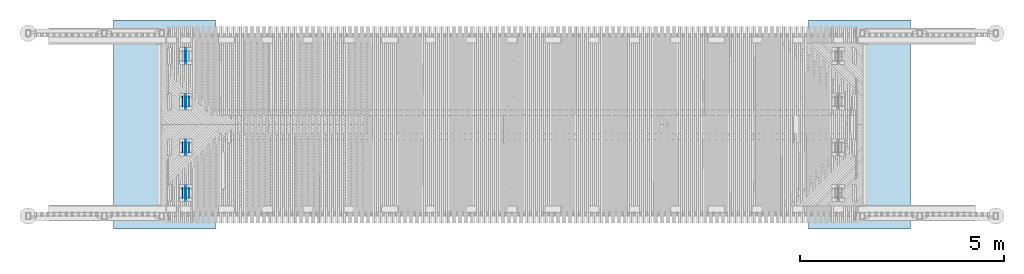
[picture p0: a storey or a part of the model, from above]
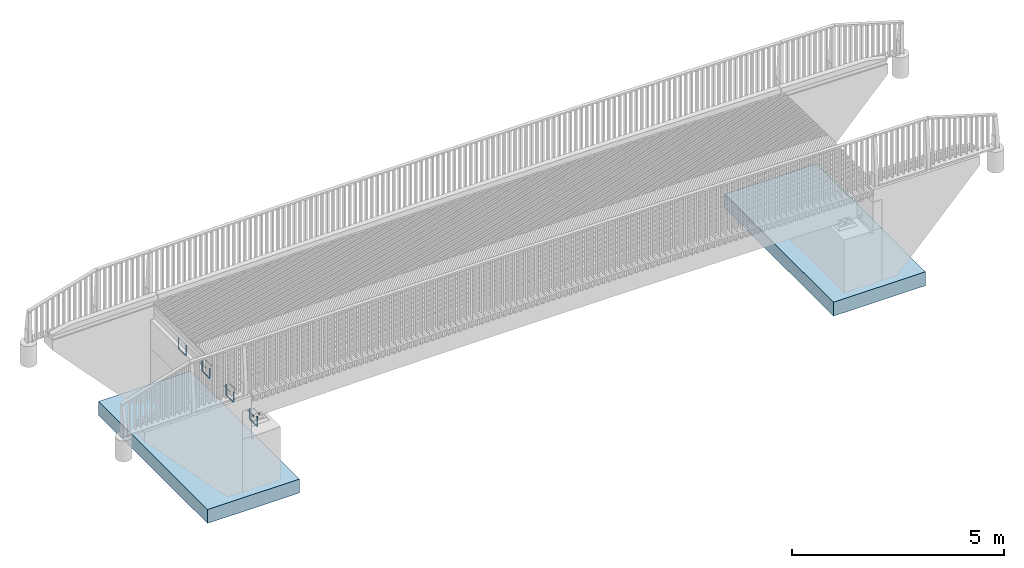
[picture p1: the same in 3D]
Properties of the parts of a building model (IFC2X3), part 2 of 2

# IfcBeam: 50*50 (546)
Name | Bottom elevation | Top elevation | Weight (kg) | Area per tons (m2) | Net surface area (m2) | Height (mm) | Tekla Quantity, Length (mm) | BaseQuantities, Length (mm) | OuterSurfaceArea (m2) | NetVolume (m3) | NetWeight (kg)
3 x BEAM | +3.165 | +3.261 | 4.1 | 135.1 | 0.7 | 50 | 2880.8 | 2880.76 | 0.572941 | 0.00707335 | 4.24401
3 x BEAM | +3.164 | +3.261 | 4.1 | 135.1 | 0.7 | 50 | 2880.8 | 2880.77 | 0.572949 | 0.0070735 | 4.2441
3 x BEAM | +3.164 | +3.261 | 4.1 | 135.1 | 0.7 | 50 | 2880.8 | 2880.76 | 0.572941 | 0.00707335 | 4.24401
3 x BEAM | +3.163 | +3.260 | 4.1 | 135.1 | 0.7 | 50 | 2880.8 | 2880.77 | 0.572949 | 0.0070735 | 4.2441
3 x BEAM | +3.163 | +3.260 | 4.1 | 135.1 | 0.7 | 50 | 2880.8 | 2880.76 | 0.572941 | 0.00707335 | 4.24401
2 x BEAM | +3.162 | +3.260 | 4.1 | 135.1 | 0.7 | 50 | 2880.8 | 2880.77 | 0.572949 | 0.0070735 | 4.2441
2 x BEAM | +3.162 | +3.260 | 4.1 | 135.1 | 0.7 | 50 | 2880.8 | 2880.76 | 0.572941 | 0.00707335 | 4.24401
2 x BEAM | +3.161 | +3.260 | 4.1 | 135.1 | 0.7 | 50 | 2880.8 | 2880.77 | 0.572949 | 0.0070735 | 4.2441
2 x BEAM | +3.161 | +3.260 | 4.1 | 135.1 | 0.7 | 50 | 2880.8 | 2880.76 | 0.572941 | 0.00707335 | 4.24401
BEAM | +3.161 | +3.259 | 4.1 | 135.1 | 0.7 | 50 | 2880.8 | 2880.77 | 0.572949 | 0.0070735 | 4.2441
BEAM | +3.161 | +3.259 | 4.1 | 135.1 | 0.7 | 50 | 2880.8 | 2880.76 | 0.572941 | 0.00707335 | 4.24401
2 x BEAM | +3.160 | +3.259 | 4.1 | 135.1 | 0.7 | 50 | 2880.8 | 2880.77 | 0.572949 | 0.0070735 | 4.2441
2 x BEAM | +3.160 | +3.259 | 4.1 | 135.1 | 0.7 | 50 | 2880.8 | 2880.76 | 0.572941 | 0.00707335 | 4.24401
2 x BEAM | +3.159 | +3.259 | 4.1 | 135.1 | 0.7 | 50 | 2880.8 | 2880.77 | 0.572949 | 0.0070735 | 4.2441
2 x BEAM | +3.159 | +3.259 | 4.1 | 135.1 | 0.7 | 50 | 2880.8 | 2880.76 | 0.572941 | 0.00707335 | 4.24401
2 x BEAM | +3.158 | +3.258 | 4.1 | 135.1 | 0.7 | 50 | 2880.8 | 2880.77 | 0.572949 | 0.0070735 | 4.2441
2 x BEAM | +3.158 | +3.258 | 4.1 | 135.1 | 0.7 | 50 | 2880.8 | 2880.76 | 0.572941 | 0.00707335 | 4.24401
3 x BEAM | +3.157 | +3.258 | 4.1 | 135.1 | 0.7 | 50 | 2880.8 | 2880.77 | 0.572949 | 0.0070735 | 4.2441
3 x BEAM | +3.157 | +3.258 | 4.1 | 135.1 | 0.7 | 50 | 2880.8 | 2880.76 | 0.572941 | 0.00707335 | 4.24401
2 x BEAM | +3.156 | +3.257 | 4.1 | 135.1 | 0.7 | 50 | 2880.8 | 2880.77 | 0.572949 | 0.0070735 | 4.2441
2 x BEAM | +3.156 | +3.257 | 4.1 | 135.1 | 0.7 | 50 | 2880.8 | 2880.76 | 0.572941 | 0.00707335 | 4.24401
BEAM | +3.155 | +3.257 | 4.1 | 135.1 | 0.7 | 50 | 2880.8 | 2880.77 | 0.572949 | 0.0070735 | 4.2441
BEAM | +3.155 | +3.257 | 4.1 | 135.1 | 0.7 | 50 | 2880.8 | 2880.76 | 0.572941 | 0.00707335 | 4.24401
BEAM | +3.154 | +3.257 | 4.1 | 135.1 | 0.7 | 50 | 2880.8 | 2880.77 | 0.572949 | 0.0070735 | 4.2441
BEAM | +3.154 | +3.257 | 4.1 | 135.1 | 0.7 | 50 | 2880.8 | 2880.76 | 0.572941 | 0.00707335 | 4.24401
BEAM | +3.154 | +3.256 | 4.1 | 135.1 | 0.7 | 50 | 2880.8 | 2880.77 | 0.572949 | 0.0070735 | 4.2441
BEAM | +3.154 | +3.256 | 4.1 | 135.1 | 0.7 | 50 | 2880.8 | 2880.76 | 0.572941 | 0.00707335 | 4.24401
2 x BEAM | +3.153 | +3.256 | 4.1 | 135.1 | 0.7 | 50 | 2880.8 | 2880.77 | 0.572949 | 0.0070735 | 4.2441
2 x BEAM | +3.153 | +3.256 | 4.1 | 135.1 | 0.7 | 50 | 2880.8 | 2880.76 | 0.572941 | 0.00707335 | 4.24401
2 x BEAM | +3.152 | +3.255 | 4.1 | 135.1 | 0.7 | 50 | 2880.8 | 2880.77 | 0.572949 | 0.0070735 | 4.2441
2 x BEAM | +3.152 | +3.255 | 4.1 | 135.1 | 0.7 | 50 | 2880.8 | 2880.76 | 0.572941 | 0.00707335 | 4.24401
BEAM | +3.151 | +3.255 | 4.1 | 135.1 | 0.7 | 50 | 2880.8 | 2880.77 | 0.572949 | 0.0070735 | 4.2441
BEAM | +3.151 | +3.255 | 4.1 | 135.1 | 0.7 | 50 | 2880.8 | 2880.76 | 0.572941 | 0.00707335 | 4.24401
BEAM | +3.151 | +3.254 | 4.1 | 135.1 | 0.7 | 50 | 2880.8 | 2880.77 | 0.572949 | 0.0070735 | 4.2441
BEAM | +3.151 | +3.254 | 4.1 | 135.1 | 0.7 | 50 | 2880.8 | 2880.76 | 0.572941 | 0.00707335 | 4.24401
BEAM | +3.150 | +3.254 | 4.1 | 135.1 | 0.7 | 50 | 2880.8 | 2880.77 | 0.572949 | 0.0070735 | 4.2441
BEAM | +3.150 | +3.254 | 4.1 | 135.1 | 0.7 | 50 | 2880.8 | 2880.76 | 0.572941 | 0.00707335 | 4.24401
BEAM | +3.149 | +3.254 | 4.1 | 135.1 | 0.7 | 50 | 2880.8 | 2880.77 | 0.572949 | 0.0070735 | 4.2441
BEAM | +3.149 | +3.254 | 4.1 | 135.1 | 0.7 | 50 | 2880.8 | 2880.76 | 0.572941 | 0.00707335 | 4.24401
BEAM | +3.149 | +3.253 | 4.1 | 135.1 | 0.7 | 50 | 2880.8 | 2880.77 | 0.572949 | 0.0070735 | 4.2441
BEAM | +3.149 | +3.253 | 4.1 | 135.1 | 0.7 | 50 | 2880.8 | 2880.76 | 0.572941 | 0.00707335 | 4.24401
2 x BEAM | +3.148 | +3.253 | 4.1 | 135.1 | 0.7 | 50 | 2880.8 | 2880.77 | 0.572949 | 0.0070735 | 4.2441
2 x BEAM | +3.148 | +3.253 | 4.1 | 135.1 | 0.7 | 50 | 2880.8 | 2880.76 | 0.572941 | 0.00707335 | 4.24401
BEAM | +3.147 | +3.252 | 4.1 | 135.1 | 0.7 | 50 | 2880.8 | 2880.77 | 0.572949 | 0.0070735 | 4.2441
BEAM | +3.147 | +3.252 | 4.1 | 135.1 | 0.7 | 50 | 2880.8 | 2880.76 | 0.572941 | 0.00707335 | 4.24401
BEAM | +3.146 | +3.252 | 4.1 | 135.1 | 0.7 | 50 | 2880.8 | 2880.77 | 0.572949 | 0.0070735 | 4.2441
BEAM | +3.146 | +3.252 | 4.1 | 135.1 | 0.7 | 50 | 2880.8 | 2880.76 | 0.572941 | 0.00707335 | 4.24401
BEAM | +3.146 | +3.251 | 4.1 | 135.1 | 0.7 | 50 | 2880.8 | 2880.77 | 0.572949 | 0.0070735 | 4.2441
BEAM | +3.146 | +3.251 | 4.1 | 135.1 | 0.7 | 50 | 2880.8 | 2880.76 | 0.572941 | 0.00707335 | 4.24401
BEAM | +3.145 | +3.251 | 4.1 | 135.1 | 0.7 | 50 | 2880.8 | 2880.77 | 0.572949 | 0.0070735 | 4.2441
BEAM | +3.145 | +3.251 | 4.1 | 135.1 | 0.7 | 50 | 2880.8 | 2880.76 | 0.572941 | 0.00707335 | 4.24401
BEAM | +3.144 | +3.251 | 4.1 | 135.1 | 0.7 | 50 | 2880.8 | 2880.77 | 0.572949 | 0.0070735 | 4.2441
BEAM | +3.144 | +3.251 | 4.1 | 135.1 | 0.7 | 50 | 2880.8 | 2880.76 | 0.572941 | 0.00707335 | 4.24401
BEAM | +3.144 | +3.250 | 4.1 | 135.1 | 0.7 | 50 | 2880.8 | 2880.77 | 0.572949 | 0.0070735 | 4.2441
BEAM | +3.144 | +3.250 | 4.1 | 135.1 | 0.7 | 50 | 2880.8 | 2880.76 | 0.572941 | 0.00707335 | 4.24401
BEAM | +3.143 | +3.250 | 4.1 | 135.1 | 0.7 | 50 | 2880.8 | 2880.77 | 0.572949 | 0.0070735 | 4.2441
BEAM | +3.143 | +3.250 | 4.1 | 135.1 | 0.7 | 50 | 2880.8 | 2880.76 | 0.572941 | 0.00707335 | 4.24401
2 x BEAM | +3.142 | +3.249 | 4.1 | 135.1 | 0.7 | 50 | 2880.8 | 2880.77 | 0.572949 | 0.0070735 | 4.2441
2 x BEAM | +3.142 | +3.249 | 4.1 | 135.1 | 0.7 | 50 | 2880.8 | 2880.76 | 0.572941 | 0.00707335 | 4.24401
BEAM | +3.141 | +3.248 | 4.1 | 135.1 | 0.7 | 50 | 2880.8 | 2880.77 | 0.572949 | 0.0070735 | 4.2441
BEAM | +3.141 | +3.248 | 4.1 | 135.1 | 0.7 | 50 | 2880.8 | 2880.76 | 0.572941 | 0.00707335 | 4.24401
BEAM | +3.140 | +3.248 | 4.1 | 135.1 | 0.7 | 50 | 2880.8 | 2880.77 | 0.572949 | 0.0070735 | 4.2441
BEAM | +3.140 | +3.248 | 4.1 | 135.1 | 0.7 | 50 | 2880.8 | 2880.76 | 0.572941 | 0.00707335 | 4.24401
BEAM | +3.140 | +3.247 | 4.1 | 135.1 | 0.7 | 50 | 2880.8 | 2880.77 | 0.572949 | 0.0070735 | 4.2441
BEAM | +3.140 | +3.247 | 4.1 | 135.1 | 0.7 | 50 | 2880.8 | 2880.76 | 0.572941 | 0.00707335 | 4.24401
BEAM | +3.139 | +3.247 | 4.1 | 135.1 | 0.7 | 50 | 2880.8 | 2880.77 | 0.572949 | 0.0070735 | 4.2441
BEAM | +3.139 | +3.247 | 4.1 | 135.1 | 0.7 | 50 | 2880.8 | 2880.76 | 0.572941 | 0.00707335 | 4.24401
BEAM | +3.138 | +3.246 | 4.1 | 135.1 | 0.7 | 50 | 2880.8 | 2880.77 | 0.572949 | 0.0070735 | 4.2441
BEAM | +3.138 | +3.246 | 4.1 | 135.1 | 0.7 | 50 | 2880.8 | 2880.76 | 0.572941 | 0.00707335 | 4.24401
BEAM | +3.137 | +3.246 | 4.1 | 135.1 | 0.7 | 50 | 2880.8 | 2880.77 | 0.572949 | 0.0070735 | 4.2441
BEAM | +3.137 | +3.246 | 4.1 | 135.1 | 0.7 | 50 | 2880.8 | 2880.76 | 0.572941 | 0.00707335 | 4.24401
BEAM | +3.137 | +3.245 | 4.1 | 135.1 | 0.7 | 50 | 2880.8 | 2880.77 | 0.572949 | 0.0070735 | 4.2441
BEAM | +3.137 | +3.245 | 4.1 | 135.1 | 0.7 | 50 | 2880.8 | 2880.76 | 0.572941 | 0.00707335 | 4.24401
BEAM | +3.136 | +3.245 | 4.1 | 135.1 | 0.7 | 50 | 2880.8 | 2880.77 | 0.572949 | 0.0070735 | 4.2441
BEAM | +3.136 | +3.245 | 4.1 | 135.1 | 0.7 | 50 | 2880.8 | 2880.76 | 0.572941 | 0.00707335 | 4.24401
BEAM | +3.135 | +3.244 | 4.1 | 135.1 | 0.7 | 50 | 2880.8 | 2880.77 | 0.572949 | 0.0070735 | 4.2441
BEAM | +3.135 | +3.244 | 4.1 | 135.1 | 0.7 | 50 | 2880.8 | 2880.76 | 0.572941 | 0.00707335 | 4.24401
BEAM | +3.134 | +3.244 | 4.1 | 135.1 | 0.7 | 50 | 2880.8 | 2880.77 | 0.572949 | 0.0070735 | 4.2441
BEAM | +3.134 | +3.244 | 4.1 | 135.1 | 0.7 | 50 | 2880.8 | 2880.76 | 0.572941 | 0.00707335 | 4.24401
BEAM | +3.134 | +3.243 | 4.1 | 135.1 | 0.7 | 50 | 2880.8 | 2880.77 | 0.572949 | 0.0070735 | 4.2441
BEAM | +3.134 | +3.243 | 4.1 | 135.1 | 0.7 | 50 | 2880.8 | 2880.76 | 0.572941 | 0.00707335 | 4.24401
BEAM | +3.133 | +3.243 | 4.1 | 135.1 | 0.7 | 50 | 2880.8 | 2880.77 | 0.572949 | 0.0070735 | 4.2441
BEAM | +3.133 | +3.243 | 4.1 | 135.1 | 0.7 | 50 | 2880.8 | 2880.76 | 0.572941 | 0.00707335 | 4.24401
BEAM | +3.132 | +3.242 | 4.1 | 135.1 | 0.7 | 50 | 2880.8 | 2880.77 | 0.572949 | 0.0070735 | 4.2441
BEAM | +3.132 | +3.242 | 4.1 | 135.1 | 0.7 | 50 | 2880.8 | 2880.76 | 0.572941 | 0.00707335 | 4.24401
BEAM | +3.131 | +3.242 | 4.1 | 135.1 | 0.7 | 50 | 2880.8 | 2880.77 | 0.572949 | 0.0070735 | 4.2441
BEAM | +3.131 | +3.242 | 4.1 | 135.1 | 0.7 | 50 | 2880.8 | 2880.76 | 0.572941 | 0.00707335 | 4.24401
BEAM | +3.130 | +3.241 | 4.1 | 135.1 | 0.7 | 50 | 2880.8 | 2880.77 | 0.572949 | 0.0070735 | 4.2441
BEAM | +3.130 | +3.241 | 4.1 | 135.1 | 0.7 | 50 | 2880.8 | 2880.76 | 0.572941 | 0.00707335 | 4.24401
BEAM | +3.129 | +3.241 | 4.1 | 135.1 | 0.7 | 50 | 2880.8 | 2880.77 | 0.572949 | 0.0070735 | 4.2441
BEAM | +3.129 | +3.241 | 4.1 | 135.1 | 0.7 | 50 | 2880.8 | 2880.76 | 0.572941 | 0.00707335 | 4.24401
BEAM | +3.129 | +3.240 | 4.1 | 135.1 | 0.7 | 50 | 2880.8 | 2880.77 | 0.572949 | 0.0070735 | 4.2441
BEAM | +3.129 | +3.240 | 4.1 | 135.1 | 0.7 | 50 | 2880.8 | 2880.76 | 0.572941 | 0.00707335 | 4.24401
BEAM | +3.128 | +3.239 | 4.1 | 135.1 | 0.7 | 50 | 2880.8 | 2880.77 | 0.572949 | 0.0070735 | 4.2441
BEAM | +3.128 | +3.239 | 4.1 | 135.1 | 0.7 | 50 | 2880.8 | 2880.76 | 0.572941 | 0.00707335 | 4.24401
BEAM | +3.127 | +3.239 | 4.1 | 135.1 | 0.7 | 50 | 2880.8 | 2880.77 | 0.572949 | 0.0070735 | 4.2441
BEAM | +3.127 | +3.239 | 4.1 | 135.1 | 0.7 | 50 | 2880.8 | 2880.76 | 0.572941 | 0.00707335 | 4.24401
BEAM | +3.126 | +3.238 | 4.1 | 135.1 | 0.7 | 50 | 2880.8 | 2880.77 | 0.572949 | 0.0070735 | 4.2441
BEAM | +3.126 | +3.238 | 4.1 | 135.1 | 0.7 | 50 | 2880.8 | 2880.76 | 0.572941 | 0.00707335 | 4.24401
BEAM | +3.125 | +3.237 | 4.1 | 135.1 | 0.7 | 50 | 2880.8 | 2880.77 | 0.572949 | 0.0070735 | 4.2441
BEAM | +3.125 | +3.237 | 4.1 | 135.1 | 0.7 | 50 | 2880.8 | 2880.76 | 0.572941 | 0.00707335 | 4.24401
BEAM | +3.124 | +3.237 | 4.1 | 135.1 | 0.7 | 50 | 2880.8 | 2880.77 | 0.572949 | 0.0070735 | 4.2441
BEAM | +3.124 | +3.237 | 4.1 | 135.1 | 0.7 | 50 | 2880.8 | 2880.76 | 0.572941 | 0.00707335 | 4.24401

# IfcBeam: 810*250 (2)
In: Undefined
Description: 810*250; Material: CONCRETE/Concrete_Undefined
Pset_BeamCommon - LoadBearing: yes; Reference: Concrete_LP-1001/0(?)
Tekla Common - Bottom elevation: +1.924; Top elevation: +2.734; Phase: 100; Class: 1009
Tekla Quantity - Weight: 2298.8 kg; Volume: 1 m3; Gross footprint area: 1.2 m2; Area per tons: 4.5 m2; Net surface area: 10.4 m2; Height: 810 mm; Width: 250 mm; Length: 4730 mm
BaseQuantities - Length: 4730 mm; OuterSurfaceArea: 10.4326 m2; NetVolume: 0.957825 m3; NetWeight: 2298.78 kg

# IfcBeam: 945*140 (9)
In: Undefined
Description: 945*140; Material: TIMBER/Timber_Undefined
Pset_BeamCommon - LoadBearing: yes; Reference: PP/0(?)
Tekla Common - Phase: 600; Class: 4011
Tekla Quantity - Weight: 71.8 kg; Volume: 0.1 m3; Gross footprint area: 0.1 m2; Area per tons: 31 m2; Net surface area: 2.2 m2; Height: 945 mm; Width: 140 mm; Length: 905 mm
BaseQuantities - Length: 905 mm; OuterSurfaceArea: 2.22845 m2; NetVolume: 0.119732 m3; NetWeight: 71.8389 kg
Name | Bottom elevation | Top elevation
2 x PALKKI | +2.030 | +2.975
4 x PALKKI | +2.028 | +2.973
3 x PALKKI | +2.070 | +3.015

# IfcBeam: 95*45 (10)
In: Undefined
Description: 95*45; Material: TIMBER/Timber_Undefined
Tekla Common - Phase: 600; Class: 8006
Tekla Quantity - Height: 95 mm; Width: 45 mm
Pset_BeamCommon - LoadBearing: yes; Reference: YJP/0(?)
Name | Bottom elevation | Top elevation | Weight (kg) | Volume (m3) = Gross footprint area (m2) | Area per tons (m2) | Net surface area (m2) | Tekla Quantity, Length (mm) | BaseQuantities, Length (mm) | OuterSurfaceArea (m2) | NetVolume (m3) | NetWeight (kg)
4 x YLÄJOHDE | +4.487 | +4.552 | 3.7 | 0 | 111.5 | 0.4 | 1450.8 | 1450.77 | 0.414591 | 0.00619936 | 3.71962
4 x YLÄJOHDE | +3.928 | +4.532 | 5 | 0 | 110.9 | 0.7 | 1959.7 | 1959.68 | 0.553875 | 0.00832025 | 4.99215
2 x YLÄJOHDE | +4.507 | +4.613 | 44 | 0.1 | 109.4 | 4.8 | 17155.2 | 17155.2 | 4.81183 | 0.0733358 | 44.0015

# IfcBeam: 990*215 (4)
In: Undefined
Description: 990*215; Material: TIMBER/Timber_Undefined
Pset_BeamCommon - LoadBearing: yes; Reference: PP/0(?)
Tekla Common - Phase: 400; Class: 4011
Tekla Quantity - Weight: 2137.4 kg; Volume: 3.6 m3; Gross footprint area: 0.1 m2; Area per tons: 19.1 m2; Net surface area: 40.8 m2; Height: 990 mm; Width: 215 mm; Length: 16892.3 mm
BaseQuantities - Length: 16892.3 mm; OuterSurfaceArea: 40.8264 m2; NetVolume: 3.5623 m3; NetWeight: 2137.38 kg
Name | Bottom elevation | Top elevation
2 x PALKKI | +1.985 | +3.025
2 x PALKKI | +2.007 | +3.047

# IfcBeam: L100*10 (16)
In: Undefined
Description: L100*10; Material: STEEL/S235JR
Pset_BeamCommon - LoadBearing: yes; Reference: P/0(?)
Tekla Common - Phase: 600; Class: 1
Tekla Quantity - Weight: 4.4 kg; Volume: 0 m3; Gross footprint area: 0 m2; Area per tons: 25.9 m2; Net surface area: 0.1 m2; Height: 100 mm; Width: 100 mm; Length: 300 mm
BaseQuantities - Length: 300 mm; OuterSurfaceArea: 0.117 m2; NetVolume: 0.00057 m3; NetWeight: 4.4745 kg
Name | Bottom elevation | Top elevation
8 x BEAM | +1.997 | +2.097
8 x BEAM | +1.975 | +2.075

# IfcBeam: PL100*10 (12)
In: Undefined
Description: PL100*10; Material: STEEL/AISI316
Pset_BeamCommon - LoadBearing: yes; Reference: KPL/0(?)
Tekla Common - Phase: 600; Class: 8013
Tekla Quantity - Weight: 1.1 kg; Volume: 0 m3; Gross footprint area: 0 m2; Area per tons: 29.8 m2; Net surface area: 0 m2; Height: 100 mm; Width: 10 mm; Length: 140 mm
BaseQuantities - Length: 140 mm; OuterSurfaceArea: 0.0328 m2; NetVolume: 0.00014 m3; NetWeight: 1.099 kg
Name | Bottom elevation | Top elevation
4 x KAIDEPYLVÄS | +3.086 | +3.096
4 x KAIDEPYLVÄS | +3.132 | +3.142
4 x KAIDEPYLVÄS | +3.113 | +3.123

# IfcBeam: PL60*10 (16)
In: Undefined
Description: PL60*10; Material: STEEL/AISI316
Tekla Common - Phase: 600; Class: 8013
Tekla Quantity - Weight: 0.5 kg; Volume: 0 m3; Gross footprint area: 0 m2; Area per tons: 31.9 m2; Net surface area: 0 m2; Height: 60 mm; Width: 10 mm; Length: 115 mm
Pset_BeamCommon - LoadBearing: yes; Reference: KPL/0(?)
BaseQuantities - Length: 115 mm; OuterSurfaceArea: 0.0173 m2; NetVolume: 0.000069 m3; NetWeight: 0.54165 kg
Name | Bottom elevation | Top elevation
4 x KAIDEPYLVÄS | +3.069 | +3.079
4 x KAIDEPYLVÄS | +3.115 | +3.125
8 x KAIDEPYLVÄS | +3.095 | +3.105

# IfcColumn: 180*100 (12)
In: Undefined
Description: 180*100; Material: TIMBER/Timber_Undefined
Tekla Common - Phase: 600; Class: 8013
Tekla Quantity - Volume: 0 m3; Gross footprint area: 0 m2; Height: 180 mm; Width: 100 mm
Pset_ColumnCommon - LoadBearing: yes; Reference: KPP/0(?)
Name | Bottom elevation | Top elevation | Weight (kg) | Area per tons (m2) | Net surface area (m2) | Tekla Quantity, Length (mm) | BaseQuantities, Length (mm) | OuterSurfaceArea (m2) | NetVolume (m3) | NetWeight (kg)
4 x KAIDEPYLVÄS | +3.123 | +4.488 | 12.1 | 58.2 | 0.7 | 1365.5 | 1365.51 | 0.703883 | 0.0201522 | 12.0913
4 x KAIDEPYLVÄS | +3.142 | +4.508 | 12.1 | 58.2 | 0.7 | 1365.5 | 1365.51 | 0.703883 | 0.0201522 | 12.0913
4 x KAIDEPYLVÄS | +3.096 | +3.958 | 7.8 | 58.6 | 0.4 | 861.7 | 861.74 | 0.459259 | 0.013053 | 7.83181

# IfcColumn: 524*639 (4)
In: Undefined
Description: 524*639; Material: CONCRETE/Concrete_Undefined
Pset_ColumnCommon - LoadBearing: yes; Reference: Concrete_P-1/0(?)
Tekla Common - Bottom elevation: +1.912; Top elevation: +1.975; Phase: 600; Class: 320
Tekla Quantity - Weight: 36.8 kg; Volume: 0 m3; Gross footprint area: 0.2 m2; Area per tons: 19 m2; Net surface area: 0.7 m2; Height: 514.8 mm; Width: 639 mm; Length: 63.5 mm
BaseQuantities - Length: 63.5137 mm; OuterSurfaceArea: 0.69991 m2; NetVolume: 0.0153352 m3; NetWeight: 36.8044 kg

# IfcColumn: 570*685 (4)
In: Undefined
Description: 570*685; Material: CONCRETE/Concrete_Undefined
Pset_ColumnCommon - LoadBearing: yes; Reference: Concrete_P-1/0(?)
Tekla Common - Bottom elevation: +1.911; Top elevation: +1.997; Phase: 600; Class: 320
Tekla Quantity - Weight: 55.5 kg; Volume: 0 m3; Gross footprint area: 0.2 m2; Area per tons: 14.9 m2; Net surface area: 0.7 m2; Height: 559.7 mm; Width: 685 mm; Length: 86 mm
BaseQuantities - Length: 85.9822 mm; OuterSurfaceArea: 0.828549 m2; NetVolume: 0.0231346 m3; NetWeight: 55.523 kg

# IfcColumn: 95*45 (302)
In: Undefined
Description: 95*45; Material: TIMBER/Timber_Undefined
Tekla Common - Phase: 600
Tekla Quantity - Volume: 0 m3; Gross footprint area: 0 m2; Net surface area: 0.4 m2; Height: 95 mm; Width: 45 mm
Pset_ColumnCommon - LoadBearing: yes
Name | Bottom elevation | Top elevation | Class | Weight (kg) | Area per tons (m2) | Tekla Quantity, Length (mm) | Reference | BaseQuantities, Length (mm) | OuterSurfaceArea (m2) | NetVolume (m3) | NetWeight (kg)
4 x BEAM | +3.150 | +4.452 | 1 | 3.3 | 111.8 | 1301.8 | P/0(?) | 1301.79 | 0.371268 | 0.00553508 | 3.32105
4 x BEAM | +3.148 | +4.407 | 1 | 3.2 | 111.8 | 1259.1 | P/0(?) | 1259.13 | 0.359326 | 0.00535274 | 3.21165
4 x BEAM | +3.146 | +4.362 | 1 | 3.1 | 112 | 1216.5 | P/0(?) | 1216.48 | 0.347383 | 0.0051704 | 3.10224
4 x BEAM | +3.144 | +4.318 | 1 | 3 | 112.1 | 1173.8 | P/0(?) | 1173.83 | 0.33544 | 0.00498806 | 2.99284
4 x BEAM | +3.142 | +4.273 | 1 | 3 | 112.1 | 1131.2 | P/0(?) | 1131.18 | 0.323498 | 0.00480573 | 2.88344
4 x BEAM | +3.140 | +4.228 | 1 | 2.8 | 112.3 | 1088.5 | P/0(?) | 1088.52 | 0.311555 | 0.00462339 | 2.77403
4 x BEAM | +3.137 | +4.183 | 1 | 2.7 | 112.3 | 1045.9 | P/0(?) | 1045.87 | 0.299612 | 0.00444105 | 2.66463
4 x BEAM | +3.135 | +4.139 | 1 | 2.6 | 112.6 | 1003.2 | P/0(?) | 1003.22 | 0.28767 | 0.00425871 | 2.55523
4 x BEAM | +3.133 | +4.094 | 1 | 2.4 | 112.6 | 960.6 | P/0(?) | 960.567 | 0.275727 | 0.00407637 | 2.44582
4 x BEAM | +3.131 | +4.049 | 1 | 2.3 | 112.9 | 917.9 | P/0(?) | 917.915 | 0.263784 | 0.00389403 | 2.33642
4 x BEAM | +3.155 | +4.490 | 1 | 3.4 | 111.7 | 1335 | P/0(?) | 1335.01 | 0.382176 | 0.00570445 | 3.42267
4 x BEAM | +3.157 | +4.492 | 1 | 3.4 | 111.7 | 1335 | P/0(?) | 1335 | 0.382175 | 0.00570444 | 3.42266
4 x BEAM | +3.159 | +4.494 | 1 | 3.4 | 111.7 | 1335 | P/0(?) | 1335 | 0.382174 | 0.00570443 | 3.42266
4 x BEAM | +3.162 | +4.497 | 1 | 3.4 | 111.7 | 1335 | P/0(?) | 1335 | 0.382174 | 0.00570442 | 3.42265
4 x BEAM | +3.164 | +4.499 | 1 | 3.4 | 111.7 | 1335 | P/0(?) | 1335 | 0.382173 | 0.00570441 | 3.42265
4 x BEAM | +3.166 | +4.501 | 1 | 3.4 | 111.7 | 1335 | P/0(?) | 1334.99 | 0.382172 | 0.0057044 | 3.42264
4 x BEAM | +3.168 | +4.503 | 1 | 3.4 | 111.7 | 1335 | P/0(?) | 1334.99 | 0.382172 | 0.00570439 | 3.42263
4 x BEAM | +3.129 | +4.004 | 1 | 2.2 | 113.1 | 875.3 | P/0(?) | 875.262 | 0.251842 | 0.00371169 | 2.22702
4 x BEAM | +3.170 | +4.505 | 1 | 3.4 | 111.7 | 1335 | P/0(?) | 1334.99 | 0.382171 | 0.00570438 | 3.42263
4 x KAIDEPYLVÄS | +2.805 | +4.510 | 8013 | 4.4 | 111.1 | 1705 | KPP/0(?) | 1705 | 0.48595 | 0.00728888 | 4.37333
4 x KAIDEPYLVÄS | +2.807 | +4.512 | 8013 | 4.4 | 111.1 | 1705 | KPP/0(?) | 1705 | 0.48595 | 0.00728888 | 4.37333
4 x KAIDEPYLVÄS | +2.809 | +4.514 | 8013 | 4.4 | 111.1 | 1705 | KPP/0(?) | 1705 | 0.48595 | 0.00728888 | 4.37333
4 x KAIDEPYLVÄS | +2.811 | +4.516 | 8013 | 4.4 | 111.1 | 1705 | KPP/0(?) | 1705 | 0.48595 | 0.00728888 | 4.37333
4 x KAIDEPYLVÄS | +2.813 | +4.518 | 8013 | 4.4 | 111.1 | 1705 | KPP/0(?) | 1705 | 0.48595 | 0.00728888 | 4.37333
4 x KAIDEPYLVÄS | +2.815 | +4.520 | 8013 | 4.4 | 111.1 | 1705 | KPP/0(?) | 1705 | 0.48595 | 0.00728888 | 4.37333
4 x KAIDEPYLVÄS | +2.817 | +4.522 | 8013 | 4.4 | 111.1 | 1705 | KPP/0(?) | 1705 | 0.48595 | 0.00728888 | 4.37333
4 x KAIDEPYLVÄS | +2.819 | +4.524 | 8013 | 4.4 | 111.1 | 1705 | KPP/0(?) | 1705 | 0.48595 | 0.00728888 | 4.37333
4 x KAIDEPYLVÄS | +2.820 | +4.525 | 8013 | 4.4 | 111.1 | 1705 | KPP/0(?) | 1705 | 0.48595 | 0.00728888 | 4.37333
4 x KAIDEPYLVÄS | +2.822 | +4.527 | 8013 | 4.4 | 111.1 | 1705 | KPP/0(?) | 1705 | 0.48595 | 0.00728888 | 4.37333
4 x KAIDEPYLVÄS | +2.824 | +4.529 | 8013 | 4.4 | 111.1 | 1705 | KPP/0(?) | 1705 | 0.48595 | 0.00728888 | 4.37333
4 x KAIDEPYLVÄS | +2.826 | +4.531 | 8013 | 4.4 | 111.1 | 1705 | KPP/0(?) | 1705 | 0.48595 | 0.00728888 | 4.37333
4 x KAIDEPYLVÄS | +2.827 | +4.532 | 8013 | 4.4 | 111.1 | 1705 | KPP/0(?) | 1705 | 0.48595 | 0.00728888 | 4.37333
4 x KAIDEPYLVÄS | +2.829 | +4.534 | 8013 | 4.4 | 111.1 | 1705 | KPP/0(?) | 1705 | 0.48595 | 0.00728888 | 4.37333
4 x KAIDEPYLVÄS | +2.830 | +4.535 | 8013 | 4.4 | 111.1 | 1705 | KPP/0(?) | 1705 | 0.48595 | 0.00728888 | 4.37333
4 x KAIDEPYLVÄS | +2.832 | +4.537 | 8013 | 4.4 | 111.1 | 1705 | KPP/0(?) | 1705 | 0.48595 | 0.00728888 | 4.37333
4 x KAIDEPYLVÄS | +2.833 | +4.538 | 8013 | 4.4 | 111.1 | 1705 | KPP/0(?) | 1705 | 0.48595 | 0.00728888 | 4.37333
4 x KAIDEPYLVÄS | +2.835 | +4.540 | 8013 | 4.4 | 111.1 | 1705 | KPP/0(?) | 1705 | 0.48595 | 0.00728888 | 4.37333
4 x KAIDEPYLVÄS | +2.836 | +4.541 | 8013 | 4.4 | 111.1 | 1705 | KPP/0(?) | 1705 | 0.48595 | 0.00728888 | 4.37333
4 x KAIDEPYLVÄS | +2.838 | +4.543 | 8013 | 4.4 | 111.1 | 1705 | KPP/0(?) | 1705 | 0.48595 | 0.00728888 | 4.37333
4 x KAIDEPYLVÄS | +2.839 | +4.544 | 8013 | 4.4 | 111.1 | 1705 | KPP/0(?) | 1705 | 0.48595 | 0.00728888 | 4.37333
4 x KAIDEPYLVÄS | +2.840 | +4.545 | 8013 | 4.4 | 111.1 | 1705 | KPP/0(?) | 1705 | 0.48595 | 0.00728888 | 4.37333
4 x KAIDEPYLVÄS | +2.842 | +4.547 | 8013 | 4.4 | 111.1 | 1705 | KPP/0(?) | 1705 | 0.48595 | 0.00728888 | 4.37333
4 x KAIDEPYLVÄS | +2.843 | +4.548 | 8013 | 4.4 | 111.1 | 1705 | KPP/0(?) | 1705 | 0.48595 | 0.00728888 | 4.37333
4 x KAIDEPYLVÄS | +2.844 | +4.549 | 8013 | 4.4 | 111.1 | 1705 | KPP/0(?) | 1705 | 0.48595 | 0.00728888 | 4.37333
4 x KAIDEPYLVÄS | +2.845 | +4.550 | 8013 | 4.4 | 111.1 | 1705 | KPP/0(?) | 1705 | 0.48595 | 0.00728888 | 4.37333
4 x KAIDEPYLVÄS | +2.847 | +4.552 | 8013 | 4.4 | 111.1 | 1705 | KPP/0(?) | 1705 | 0.48595 | 0.00728888 | 4.37333
4 x KAIDEPYLVÄS | +2.848 | +4.553 | 8013 | 4.4 | 111.1 | 1705 | KPP/0(?) | 1705 | 0.48595 | 0.00728888 | 4.37333
4 x KAIDEPYLVÄS | +2.849 | +4.554 | 8013 | 4.4 | 111.1 | 1705 | KPP/0(?) | 1705 | 0.48595 | 0.00728888 | 4.37333
4 x KAIDEPYLVÄS | +2.850 | +4.555 | 8013 | 4.4 | 111.1 | 1705 | KPP/0(?) | 1705 | 0.48595 | 0.00728888 | 4.37333
4 x KAIDEPYLVÄS | +2.851 | +4.556 | 8013 | 4.4 | 111.1 | 1705 | KPP/0(?) | 1705 | 0.48595 | 0.00728888 | 4.37333
4 x KAIDEPYLVÄS | +2.852 | +4.557 | 8013 | 4.4 | 111.1 | 1705 | KPP/0(?) | 1705 | 0.48595 | 0.00728888 | 4.37333
8 x KAIDEPYLVÄS | +2.853 | +4.558 | 8013 | 4.4 | 111.1 | 1705 | KPP/0(?) | 1705 | 0.48595 | 0.00728888 | 4.37333
4 x KAIDEPYLVÄS | +2.854 | +4.559 | 8013 | 4.4 | 111.1 | 1705 | KPP/0(?) | 1705 | 0.48595 | 0.00728888 | 4.37333
4 x KAIDEPYLVÄS | +2.855 | +4.560 | 8013 | 4.4 | 111.1 | 1705 | KPP/0(?) | 1705 | 0.48595 | 0.00728888 | 4.37333
4 x KAIDEPYLVÄS | +2.856 | +4.561 | 8013 | 4.4 | 111.1 | 1705 | KPP/0(?) | 1705 | 0.48595 | 0.00728888 | 4.37333
8 x KAIDEPYLVÄS | +2.857 | +4.562 | 8013 | 4.4 | 111.1 | 1705 | KPP/0(?) | 1705 | 0.48595 | 0.00728888 | 4.37333
4 x KAIDEPYLVÄS | +2.858 | +4.563 | 8013 | 4.4 | 111.1 | 1705 | KPP/0(?) | 1705 | 0.48595 | 0.00728888 | 4.37333
8 x KAIDEPYLVÄS | +2.859 | +4.564 | 8013 | 4.4 | 111.1 | 1705 | KPP/0(?) | 1705 | 0.48595 | 0.00728888 | 4.37333
8 x KAIDEPYLVÄS | +2.860 | +4.565 | 8013 | 4.4 | 111.1 | 1705 | KPP/0(?) | 1705 | 0.48595 | 0.00728888 | 4.37333
12 x KAIDEPYLVÄS | +2.861 | +4.566 | 8013 | 4.4 | 111.1 | 1705 | KPP/0(?) | 1705 | 0.48595 | 0.00728888 | 4.37333
12 x KAIDEPYLVÄS | +2.862 | +4.567 | 8013 | 4.4 | 111.1 | 1705 | KPP/0(?) | 1705 | 0.48595 | 0.00728888 | 4.37333
26 x KAIDEPYLVÄS | +2.863 | +4.568 | 8013 | 4.4 | 111.1 | 1705 | KPP/0(?) | 1705 | 0.48595 | 0.00728888 | 4.37333

# IfcColumn: D33 (16)
In: Undefined
Description: D33; Material: STEEL/Steel_Undefined
Pset_ColumnCommon - LoadBearing: yes; Reference: P/0(?)
Tekla Common - Phase: 600; Class: 1
Tekla Quantity - Weight: 0.1 kg; Volume: 0 m3; Gross footprint area: 0 m2; Area per tons: 30.1 m2; Net surface area: 0 m2; Height: 33 mm; Width: 33 mm; Length: 18 mm
BaseQuantities - Length: 18 mm; OuterSurfaceArea: 0.00347836 m2; NetVolume: 0.0000147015 m3; NetWeight: 0.115407 kg
Name | Bottom elevation | Top elevation
8 x BEAM | +2.015 | +2.033
8 x BEAM | +1.993 | +2.011

# IfcColumn: D38 (16)
In: Undefined
Description: D38; Material: STEEL/Steel_Undefined
Pset_ColumnCommon - LoadBearing: yes; Reference: P/0(?)
Tekla Common - Phase: 600; Class: 1
Tekla Quantity - Weight: 0.1 kg; Volume: 0 m3; Gross footprint area: 0 m2; Area per tons: 45.7 m2; Net surface area: 0 m2; Height: 38 mm; Width: 38 mm; Length: 8 mm
BaseQuantities - Length: 8 mm; OuterSurfaceArea: 0.00311017 m2; NetVolume: 0.000008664 m3; NetWeight: 0.0680124 kg
Name | Bottom elevation | Top elevation
8 x BEAM | +2.007 | +2.015
8 x BEAM | +1.985 | +1.993

# IfcColumn: D400 (4)
In: Undefined
Description: D400; Material: CONCRETE/Concrete_Undefined
Tekla Common - Bottom elevation: +2.446; Top elevation: +3.046; Phase: 600; Class: 320
Tekla Quantity - Weight: 180 kg; Volume: 0.1 m3; Gross footprint area: 0.1 m2; Area per tons: 5.6 m2; Net surface area: 1 m2; Height: 400 mm; Width: 400 mm; Length: 600 mm
Pset_ColumnCommon - LoadBearing: yes; Reference: Concrete_P-1/0(?)
BaseQuantities - Length: 600 mm; OuterSurfaceArea: 1.00308 m2; NetVolume: 0.075016 m3; NetWeight: 180.038 kg

# IfcColumn: PL150*10 (24)
In: Undefined
Description: PL150*10; Material: STEEL/AISI316
Tekla Common - Phase: 600; Class: 8013
Tekla Quantity - Weight: 6.8 kg; Volume: 0 m3; Gross footprint area: 0 m2; Area per tons: 27.7 m2; Net surface area: 0.2 m2; Height: 150 mm; Width: 10 mm; Length: 620 mm
Pset_ColumnCommon - LoadBearing: yes; Reference: KPL/0(?)
BaseQuantities - Length: 620 mm; OuterSurfaceArea: 0.1889 m2; NetVolume: 0.0008675 m3; NetWeight: 6.80988 kg
Name | Bottom elevation | Top elevation
8 x KAIDEPYLVÄS | +2.796 | +3.416
8 x KAIDEPYLVÄS | +2.842 | +3.462
8 x KAIDEPYLVÄS | +2.823 | +3.443

# IfcColumn: PL300*215 (8)
In: Undefined
Description: PL300*215; Material: MISCELLANEOUS/NEOPREENI
Pset_ColumnCommon - LoadBearing: yes; Reference: P/0(?)
Tekla Common - Phase: 600; Class: 7
Tekla Quantity - Weight: 1 kg; Volume: 0 m3; Gross footprint area: 0.1 m2; Area per tons: 154.3 m2; Net surface area: 0.1 m2; Height: 300 mm; Width: 215 mm; Length: 10 mm
BaseQuantities - Length: 10 mm; OuterSurfaceArea: 0.1393 m2; NetVolume: 0.000645 m3; NetWeight: 0.903 kg
Name | Bottom elevation | Top elevation
4 x COLUMN | +1.975 | +1.985
4 x COLUMN | +1.997 | +2.007

# IfcMechanicalFastener: Bolt assembly (24)
In: Undefined
NominalDiameter: 20 mm; Material: Undefined
Tekla Bolt - Washer diameter: 20 mm; Washer type: DIN125; Washer name: W20-DIN125; Nut type: DIN934; Nut name: M20-DIN934; Slotted hole y: 0 mm; Location: Site
Name | NominalLength (mm) = Bolt length (mm) | Washer count | Nut count | Slotted hole x (mm) | Bolt hole diameter (mm) | Bolt count | Bolt size (mm) | Bolt standard | Bolt Name
16 x Bolt assembly | 30 | 0 | 0 | 30 | 30 | 1 | 30 | DIN933 | M20*30
8 x Bolt assembly | 270 | 4 | 2 | 0 | 22 | 2 | 20 | DIN931 | M20*270

# IfcReinforcingBar (16)
In: Undefined
NominalDiameter: 23 mm; CrossSectionArea: 0 m2; Material: A500HW
Tekla Reinforcement - TD: 40 mm; r: 20 mm; c: 311 mm; b: 378 mm; a: 311 mm; Length: 920 mm; Total Weight: 2.3 kg; Weight: 2.3 kg; Cast unit mark: LP/0(?); Phase: 100; Total Number: 1; Grade: A500HW; Name: REBAR; Size: 20; Rebar Mark: 0(?); Shape: D

# IfcSlab: 400*2500 (2)
In: Undefined
Description: 400*2500; PredefinedType: FLOOR; Material: CONCRETE/Concrete_Undefined
Tekla Common - Bottom elevation: +0.000; Top elevation: +0.400; Phase: 100; Class: 1003
Tekla Quantity - Weight: 12312 kg; Volume: 5.1 m3; Gross footprint area: 12.8 m2; Area per tons: 2.6 m2; Net surface area: 31.8 m2; Height: 2500 mm; Width: 400 mm; Length: 5130 mm
Pset_SlabCommon - LoadBearing: yes; Reference: Concrete_PL-1/0(?)
BaseQuantities - Width: 400 mm; NetVolume: 5.13 m3; NetArea: 12.825 m2; NetWeight: 12312 kg
